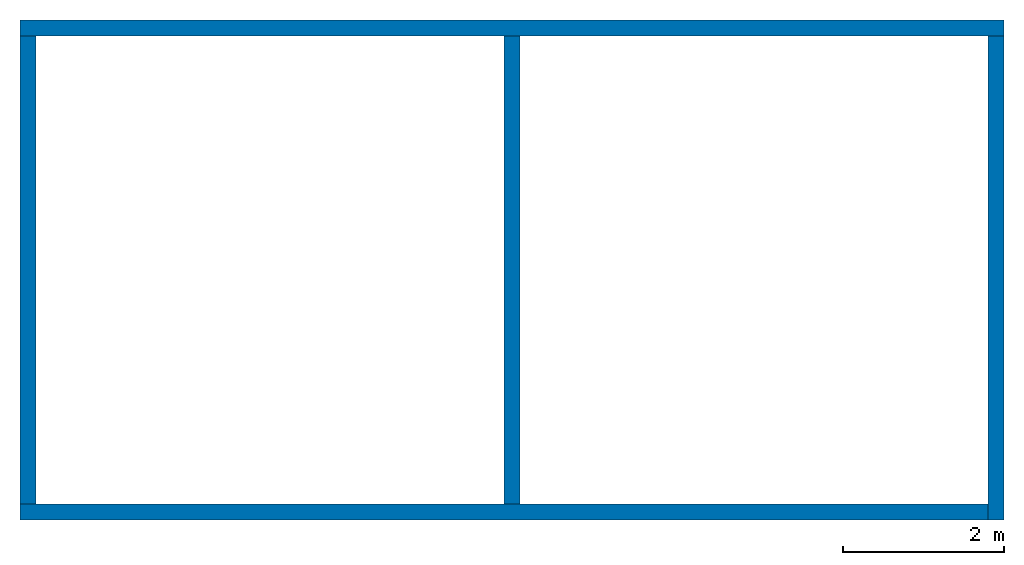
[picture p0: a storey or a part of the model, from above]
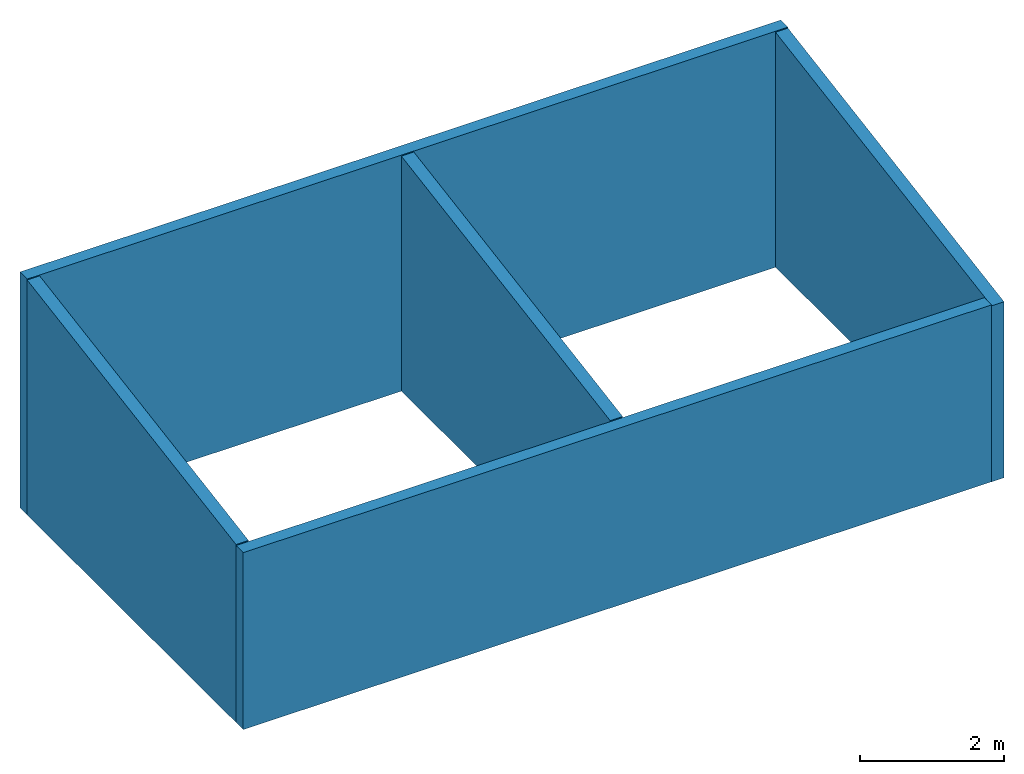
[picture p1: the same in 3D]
Properties of the parts of a building model (IFC2X3)

# File
Description: ViewDefinition [CoordinationView]
File name: Numéro du projet
Time: 2015-03-07T22:38:24
Written by: The EXPRESS Data Manager Version 5.02.0100.07 : 28 Aug 2013
Made in: 20140223_1515(x64) - Exporter 2015.0.2014.0223 - Default UI
Comment: STEP Physical File produced by: The EXPRESS Data Manager Version 5.02.0100.07 : 28 Aug 2013 * Module: EDMstepFileFactory/EDMstandAlone * Creation date: Sat Mar 07 22:38:24 2015 * Host: vincent-HP * Database: C:\Users\vincent\AppData\Local\Temp\{8342DAB2-6A58-4D15-93FE-BD74B7376A37}\ifc * Database version: 5507 * Database creation date: Sat Mar 07 22:38:23 2015 * Schema: IFC2X3 * Model: DataRepository.ifc * Model creation date: Sat Mar 07 22:38:23 2015 * Header model: DataRepository.ifc_HeaderModel * Header model creation date: Sat Mar 07 22:38:23 2015 * EDMuser: sdai-user * EDMgroup: sdai-group * License ID and type: 5605 : Permanent license. Expiry date: * EDMstepFileFactory options: 020000

# IfcProject, Numéro du projet
LongName: Nom du projet; Phase: Etat du projet

# IfcSite, Default
RefLatitude: 48, 51, 23, 999633; RefLongitude: 2, 21, 3, 553905; RefElevation: 0 m
Autre - Adresse du projet: Entrer l'adresse ici; Catégorie: Informations sur le projet; Date de fin du projet: Date de fin; Etat du projet: Etat du projet; Nom du client: Propriétaire; Nom du projet: Nom du projet; Numéro de projet: Numéro du projet

# IfcBuilding
Pset_BuildingCommon - NumberOfStoreys: 1
Autre - Catégorie: Informations sur le projet; Adresse du projet: Entrer l'adresse ici; Date de fin du projet: Date de fin; Etat du projet: Etat du projet; Nom du client: Propriétaire; Nom du projet: Nom du projet; Numéro de projet: Numéro du projet

# IfcBuildingStorey, Niveau 0
LongName: Niveau 0; Elevation: -1.94916e-14 m
Autre - Catégorie: Niveaux; Famille: Niveau: Ligne du Niveau; Famille et type: Niveau: Ligne du Niveau; ID du type: Niveau: Ligne du Niveau; Type: Niveau: Ligne du Niveau; Nom de la famille: Niveau
Contraintes - Elévation: 0 m; Base de l'élévation: Point de base du projet
Cotes - Hauteur de calcul: 0 m
Données d'identification - Structure: no; Etage de bâtiment: yes; Nom: Niveau 0; Nom du type: Ligne du Niveau
Graphismes - Couleur: 12632256; Epaisseur des lignes: 1; Motif des lignes: Tiret point; Symbole: Marqueur de niveau - Point triangulaire: Marqueur de niveau - Point triangulaire; Valeur par défaut du symbole à l'extrémité 1: no; Valeur par défaut du symbole à l'extrémité 2: yes

# IfcWallStandardCase: Mur de base:Ext. Voile BA 20 (5)
In: Niveau 0
Type - PredefinedType: STANDARD; Material: Maçonnerie - Voile BA 0.2 m
Type - Autre - Catégorie: Murs; Nom de la famille: Mur de base
Type - Construction - Fonction: Extérieur; Largeur: 0.2 m; Retournement aux extrémités: Aucun(e); Retournement aux insertions: Ne pas retourner
Type - Données d'identification - Commentaires du type: Extérieur voile BA 20; Nom du type: Ext. Voile BA 20
Type - Graphismes - Couleur vue détail faible: 0
Type - Matériaux et finitions - Matériau structurel: Maçonnerie - Voile BA
Type - Propriétés analytiques - Coefficient d'absorbance: 0.7; Rugosité: 3
Autre - Famille: Mur de base: Ext. Voile BA 20; Famille et type: Mur de base: Ext. Voile BA 20; ID du type: Mur de base: Ext. Voile BA 20; Type: Mur de base: Ext. Voile BA 20
Contraintes - Contrainte inférieure: Niveau: Niveau 0; Décalage inférieur: 0 m; Décalage supérieur: 0 m; Extension inférieure: 0 m; Extension supérieure: 0 m; Lié au volume: no; Ligne de justification: Axe du mur; Limite de pièce: yes; Partie inférieure attachée: no; Partie supérieure attachée: no
Phase de construction - Phase de création: Nouvelle construction
Pset_WallCommon - Reference: Ext. Voile BA 20; ExtendToStructure: no; IsExternal: yes
Name (Mur de base:Ext. Voile BA 20:...) | Contrainte supérieure | Hauteur non contrainte (m) | Longueur (m) | Surface (m2) | Volume (m3) | Activer le modèle analytique = Structure = LoadBearing | Enrobage d'armature - Autres faces = Enrobage d'armature - Face extérieure = Enrobage d'armature - Face intérieure | Utilisation structurelle
234480 | Niveau: Niveau 2 | 4 | 12 | 48.8 | 9.76 | yes | Paramètres de l'enrobage d'armature: Enrobage d'armature 1 | Porteur
234516 | Niveau: Niveau 2 | 4 | 6 | 20.9 | 4.18 | yes | Paramètres de l'enrobage d'armature: Enrobage d'armature 1 | Porteur
234576 | Niveau: Niveau 1 | 3 | 12 | 36 | 7.2 | yes | Paramètres de l'enrobage d'armature: Enrobage d'armature 1 | Porteur
234664 | Niveau: Niveau 2 | 4 | 6 | 20.3 | 4.06 | no |  | Non porteur
235427 | Niveau: Niveau 2 | 4 | 6 | 20.3 | 4.06 | yes | Paramètres de l'enrobage d'armature: Enrobage d'armature 1 | Porteur
